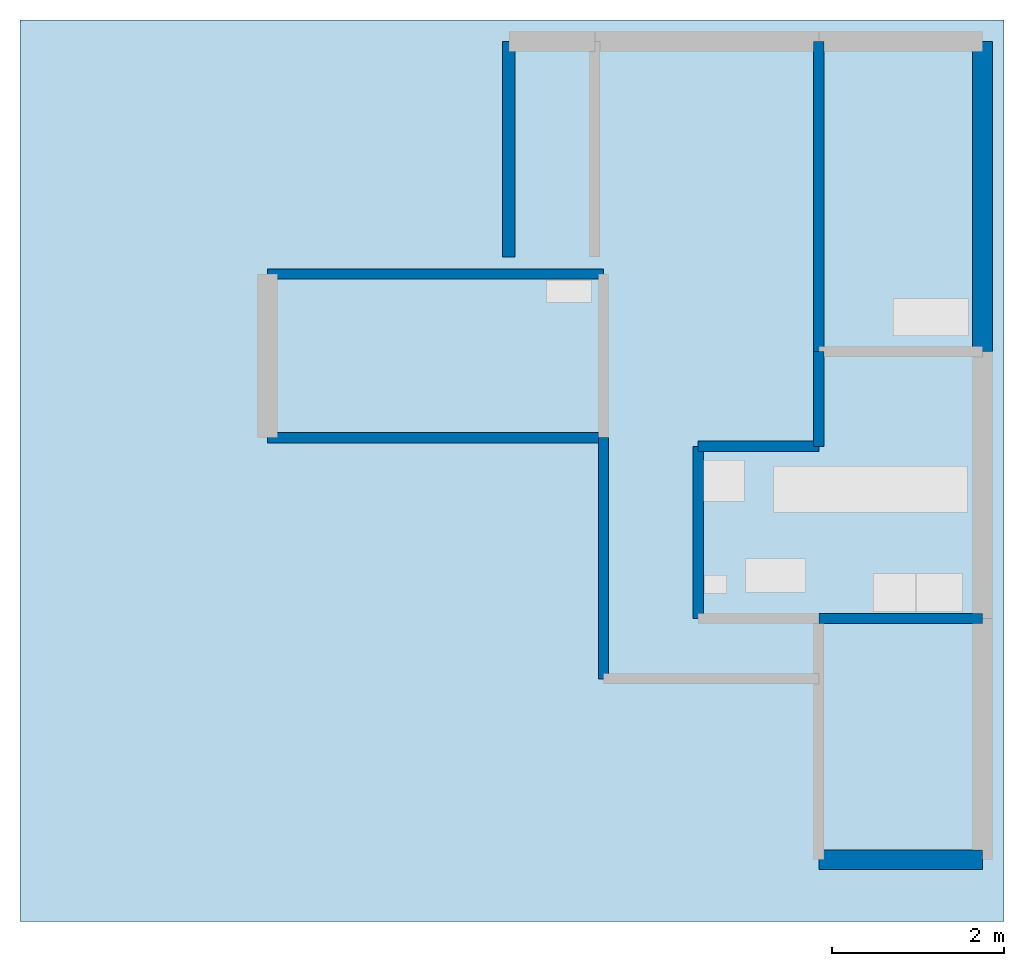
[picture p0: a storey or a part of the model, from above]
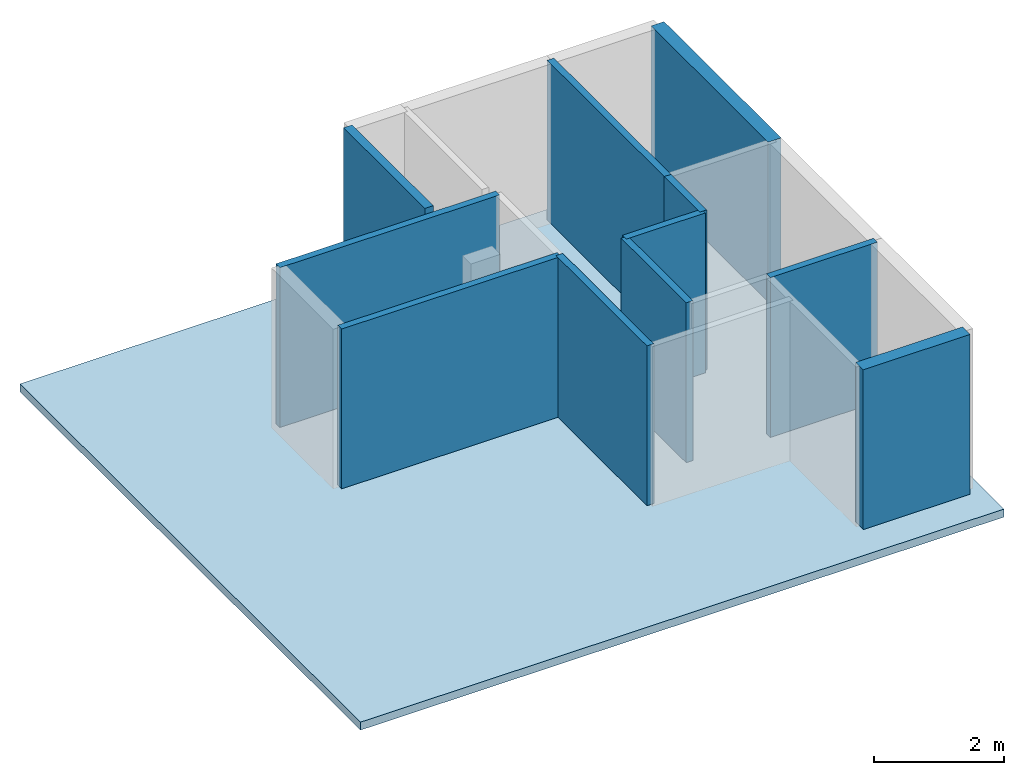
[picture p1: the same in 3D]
Properties of the parts of a building model (IFC4)

# File
Description: ViewDefinition [CoordinationView]
Time: 2026-06-09T21:47:04
Written by: IfcOpenShell 0.8.4-e8eb5e4
Made in: IfcOpenShell 0.8.4-e8eb5e4

# IfcDoor (7)
In: Ground Floor
OverallHeight: 2.1 m; PredefinedType: DOOR; Material: Wood
Pset_DoorCommon - OperationType: SINGLE_SWING_RIGHT; OverallHeight: 2.1 m; Material: Wood; Finish: Painted; IsExternal: no; SecurityRating: Medium; DoorLeafs: 1; ThresholdHeight: 0.05 m; IsAccessible: yes; Color: #66331A
Name | OverallWidth (m) = Pset_DoorCommon, OverallWidth (m) | OperationType
door_main | 1 | SINGLE_SWING_RIGHT
door_balc_tl | 0.8 | SINGLE_SWING_LEFT
door_bed_ml | 0.9 | SINGLE_SWING_RIGHT
door_bed_tr | 0.9 | SINGLE_SWING_LEFT
door_bath | 0.7 | SINGLE_SWING_RIGHT
door_bed_br | 0.8 | SINGLE_SWING_LEFT
door_corridor_ext | 0.8 | SINGLE_SWING_RIGHT

# IfcElectricAppliance, stove_01
In: Ground Floor
PredefinedType: ELECTRICCOOKER; Material: Glass/Steel
Pset_ElectricApplianceTypeCommon - ApplianceType: ELECTRICCOOKER; PowerRating: 1000; Voltage: 230; Color: #1A1A1A; Manufacturer: LG; ModelNumber: Standard Model; EnergyRating: 3 Star; OverallWidth: 0.6 m; OverallDepth: 0.5 m; OverallHeight: 0.15 m; Material: Glass/Steel; BurnerCount: 4
Pset_GasStoveTypeCommon - BurnerCount: 3 Burner; FuelType: LPG; StoveType: Glass Top; AutoIgnition: yes; HasGrids: yes

# IfcFurniture (3)
In: Ground Floor
PredefinedType: SHELF
Pset_FurnitureTypeCommon - FurnitureType: SHELF; Style: Modern; Finish: Laminate; Manufacturer: Urban Ladder; ModelNumber: Standard; Weight: 50; WarrantyYears: 2; AssemblyRequired: no
Pset_CabinetTypeCommon - NumberOfShelves: 3; NumberOfDoors: 2; DoorType: Sliding; CableManagement: no; MountingType: Floor-mounted; HasMirror: no; HasLock: no; InteriorFinish: Laminate
Pset_WardrobeTypeCommon - NumberOfDoors: 3; DoorType: Sliding; HasMirror: yes; InternalLayout: With Drawers; NumberOfShelves: 4; NumberOfDrawers: 2; HasHangingRod: yes; LockType: Handle Lock; BodyMaterial: MDF
Name | Material = Pset_FurnitureTypeCommon, Material | Color | OverallWidth (m) | OverallDepth (m) | OverallHeight (m)
wardrobe_tr | Wood | #996633 | 1.2 | 0.6 | 2.1
wardrobe_ml | Wood | #996633 | 0.8 | 0.4 | 2.1
kitchen_counter | Granite | #333333 | 2.5 | 0.6 | 0.85

# IfcSanitaryTerminal (4)
In: Ground Floor
Pset_SanitaryTerminalTypeCommon - Mounting: Wall-hung; MountingType: Wall-hung; FlushType: Dual Flush; SpigotPosition: Back; BowlCount: 1; HasDrainer: no; TrayMaterial: Acrylic; DrainDiameter: 0.05 m; WaterCapacity: 150; Shape: Built-in; WaterResistance: High; Manufacturer: Jaquar; InstallationHeight: 0.85 m
Name | PredefinedType = SanitaryTerminalType | Material = Pset_SanitaryTerminalTypeCommon, Material | Color | OverallWidth (m) | OverallDepth (m) | OverallHeight (m)
wc_01 | TOILETPAN | Ceramic | #FFFFFF | 0.7 | 0.4 | 0.4
basin_01 | WASHHANDBASIN | Ceramic | #FFFFFF | 0.5 | 0.4 | 0.8
shower_01 | SHOWER | Chrome | #CCCCCC | 0.9 | 0.9 | 2.1
sink_01 | SINK | Stainless Steel | #B2B2B2 | 0.6 | 0.5 | 0.2

# IfcSlab, slab_ground
In: Ground Floor
PredefinedType: FLOOR; Material: RCC
Pset_SlabCommon - Material: RCC; Thickness: 150 m; Finish: Smooth; IsExternal: no; LoadBearing: yes

# IfcWallStandardCase (23)
In: Ground Floor
Pset_WallCommon - Material: Brick; Height: 3 m; OverallHeight: 3 m; IsExternal: no; LoadBearing: yes; Finish: Plaster
BaseQuantities - Height: 3 m
ArchiCADQuantities - Höhe: 3 m; Maximale Höhe der Wand: 3 m; Minimale Höhe der Wand: 3 m
Name | Thickness (m) = Pset_WallCommon, Width (m) = OverallWidth (m) = BaseQuantities, Width (m) = Dicke (m) | Length (m) = Länge der Wand in der Achse (m) | GrossFootprintArea (m) = NetFootprintArea (m) = Fläche (m) | GrossVolume (m) = NetVolume (m) = Netto-Volumen (m) | Name | Wandlänge an der Außenseite (m) | Wandlänge an der Innenseite (m)
wall_ext_top_left | 0.23 | 1 | 0.23 | 0.69 | wall_ext_top_left | 1.23 | 0.77
wall_ext_top_living | 0.23 | 2.6 | 0.598 | 1.794 | wall_ext_top_living | 2.83 | 2.37
wall_ext_top_right | 0.23 | 1.9 | 0.437 | 1.311 | wall_ext_top_right | 2.13 | 1.67
wall_ext_right_top | 0.23 | 3.6 | 0.828 | 2.484 | wall_ext_right_top | 3.83 | 3.37
wall_ext_right_mid | 0.23 | 3.1 | 0.713 | 2.139 | wall_ext_right_mid | 3.33 | 2.87
wall_ext_right_bot | 0.23 | 2.8 | 0.644 | 1.932 | wall_ext_right_bot | 3.03 | 2.57
wall_ext_bot_right | 0.23 | 1.9 | 0.437 | 1.311 | wall_ext_bot_right | 2.13 | 1.67
wall_int_bed_tr_bot | 0.12 | 1.9 | 0.228 | 0.684 | wall_int_bed_tr_bot | 2.02 | 1.78
wall_int_living_bed_tr | 0.12 | 3.6 | 0.432 | 1.296 | wall_int_living_bed_tr | 3.72 | 3.48
wall_int_living_kitchen | 0.12 | 1.1 | 0.132 | 0.396 | wall_int_living_kitchen | 1.22 | 0.98
wall_int_bath_top | 0.12 | 1.4 | 0.168 | 0.504 | wall_int_bath_top | 1.52 | 1.28
wall_int_bath_left | 0.12 | 2 | 0.24 | 0.72 | wall_int_bath_left | 2.12 | 1.88
wall_int_bath_bot | 0.12 | 1.4 | 0.168 | 0.504 | wall_int_bath_bot | 1.52 | 1.28
wall_int_kitchen_bot | 0.12 | 1.9 | 0.228 | 0.684 | wall_int_kitchen_bot | 2.02 | 1.78
wall_int_bed_br_left | 0.12 | 2.8 | 0.336 | 1.008 | wall_int_bed_br_left | 2.92 | 2.68
wall_int_corridor_bot | 0.12 | 2.5 | 0.3 | 0.9 | wall_int_corridor_bot | 2.62 | 2.38
wall_int_corridor_left | 0.12 | 2.8 | 0.336 | 1.008 | wall_int_corridor_left | 2.92 | 2.68
wall_int_bed_ml_top | 0.12 | 3.9 | 0.468 | 1.404 | wall_int_bed_ml_top | 4.02 | 3.78
wall_ext_bed_ml_left | 0.23 | 1.9 | 0.437 | 1.311 | wall_ext_bed_ml_left | 2.13 | 1.67
wall_int_bed_ml_bot | 0.12 | 3.9 | 0.468 | 1.404 | wall_int_bed_ml_bot | 4.02 | 3.78
wall_int_bed_ml_right | 0.12 | 1.9 | 0.228 | 0.684 | wall_int_bed_ml_right | 2.02 | 1.78
wall_ext_balc_tl_left | 0.15 | 2.5 | 0.375 | 1.125 | wall_ext_balc_tl_left | 2.65 | 2.35
wall_int_balc_tl_right | 0.12 | 2.5 | 0.3 | 0.9 | wall_int_balc_tl_right | 2.62 | 2.38

# IfcWindow (5)
In: Ground Floor
PredefinedType: WINDOW; Material: Aluminium
Pset_WindowCommon - OperationType: SLIDING; Material: Aluminium; FrameMaterial: Aluminium; GlazingType: Double; ThermalTransmittance: 3; UValue: 2.5; CillHeight: 0.9 m; IsExternal: yes; Color: #CCCCE6
Name | OverallHeight (m) = Pset_WindowCommon, OverallHeight (m) | OverallWidth (m) = Pset_WindowCommon, OverallWidth (m) | PartitioningType
win_balc_tl | 1.2 | 0.8 | DOUBLE_PANEL_HORIZONTAL
win_bed_tr | 1.2 | 1.5 | DOUBLE_PANEL_HORIZONTAL
win_bed_ml | 1.2 | 1.2 | DOUBLE_PANEL_HORIZONTAL
win_kitchen | 1 | 1 | SINGLE_PANEL
win_bed_br | 1.2 | 1.2 | DOUBLE_PANEL_HORIZONTAL
